##
## LEF for PtnCells ;
## created by Innovus v15.23-s045_1 on Mon Mar  9 14:37:11 2026
##

VERSION 5.8 ;

BUSBITCHARS "[]" ;
DIVIDERCHAR "/" ;

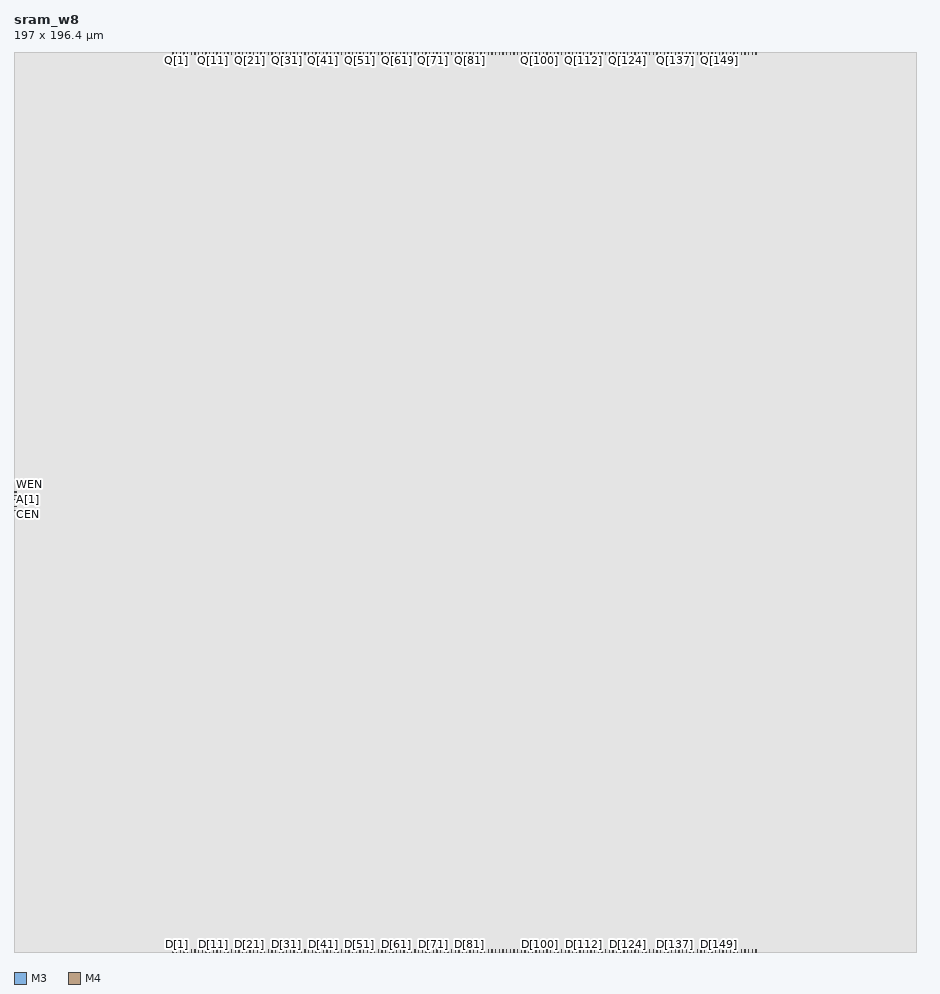
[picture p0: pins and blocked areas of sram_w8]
MACRO sram_w8
  CLASS BLOCK ;
  SIZE 197.0000 BY 196.4000 ;
  FOREIGN sram_w8 0.0000 0.0000 ;
  ORIGIN 0 0 ;
  SYMMETRY X Y R90 ;
  PIN CLK
    DIRECTION INPUT ;
    USE SIGNAL ;
    PORT
      LAYER M3 ;
        RECT 0.0000 96.3500 0.6000 96.4500 ;
    END
  END CLK
  PIN D[159]
    DIRECTION INPUT ;
    USE SIGNAL ;
    PORT
      LAYER M4 ;
        RECT 161.8500 0.0000 161.9500 0.6000 ;
    END
  END D[159]
  PIN D[158]
    DIRECTION INPUT ;
    USE SIGNAL ;
    PORT
      LAYER M4 ;
        RECT 161.0500 0.0000 161.1500 0.6000 ;
    END
  END D[158]
  PIN D[157]
    DIRECTION INPUT ;
    USE SIGNAL ;
    PORT
      LAYER M4 ;
        RECT 160.2500 0.0000 160.3500 0.6000 ;
    END
  END D[157]
  PIN D[156]
    DIRECTION INPUT ;
    USE SIGNAL ;
    PORT
      LAYER M4 ;
        RECT 159.4500 0.0000 159.5500 0.6000 ;
    END
  END D[156]
  PIN D[155]
    DIRECTION INPUT ;
    USE SIGNAL ;
    PORT
      LAYER M4 ;
        RECT 158.6500 0.0000 158.7500 0.6000 ;
    END
  END D[155]
  PIN D[154]
    DIRECTION INPUT ;
    USE SIGNAL ;
    PORT
      LAYER M4 ;
        RECT 157.8500 0.0000 157.9500 0.6000 ;
    END
  END D[154]
  PIN D[153]
    DIRECTION INPUT ;
    USE SIGNAL ;
    PORT
      LAYER M4 ;
        RECT 157.0500 0.0000 157.1500 0.6000 ;
    END
  END D[153]
  PIN D[152]
    DIRECTION INPUT ;
    USE SIGNAL ;
    PORT
      LAYER M4 ;
        RECT 156.2500 0.0000 156.3500 0.6000 ;
    END
  END D[152]
  PIN D[151]
    DIRECTION INPUT ;
    USE SIGNAL ;
    PORT
      LAYER M4 ;
        RECT 155.4500 0.0000 155.5500 0.6000 ;
    END
  END D[151]
  PIN D[150]
    DIRECTION INPUT ;
    USE SIGNAL ;
    PORT
      LAYER M4 ;
        RECT 154.6500 0.0000 154.7500 0.6000 ;
    END
  END D[150]
  PIN D[149]
    DIRECTION INPUT ;
    USE SIGNAL ;
    PORT
      LAYER M4 ;
        RECT 153.8500 0.0000 153.9500 0.6000 ;
    END
  END D[149]
  PIN D[148]
    DIRECTION INPUT ;
    USE SIGNAL ;
    PORT
      LAYER M4 ;
        RECT 153.0500 0.0000 153.1500 0.6000 ;
    END
  END D[148]
  PIN D[147]
    DIRECTION INPUT ;
    USE SIGNAL ;
    PORT
      LAYER M4 ;
        RECT 152.2500 0.0000 152.3500 0.6000 ;
    END
  END D[147]
  PIN D[146]
    DIRECTION INPUT ;
    USE SIGNAL ;
    PORT
      LAYER M4 ;
        RECT 151.4500 0.0000 151.5500 0.6000 ;
    END
  END D[146]
  PIN D[145]
    DIRECTION INPUT ;
    USE SIGNAL ;
    PORT
      LAYER M4 ;
        RECT 150.6500 0.0000 150.7500 0.6000 ;
    END
  END D[145]
  PIN D[144]
    DIRECTION INPUT ;
    USE SIGNAL ;
    PORT
      LAYER M4 ;
        RECT 149.8500 0.0000 149.9500 0.6000 ;
    END
  END D[144]
  PIN D[143]
    DIRECTION INPUT ;
    USE SIGNAL ;
    PORT
      LAYER M4 ;
        RECT 149.0500 0.0000 149.1500 0.6000 ;
    END
  END D[143]
  PIN D[142]
    DIRECTION INPUT ;
    USE SIGNAL ;
    PORT
      LAYER M4 ;
        RECT 148.2500 0.0000 148.3500 0.6000 ;
    END
  END D[142]
  PIN D[141]
    DIRECTION INPUT ;
    USE SIGNAL ;
    PORT
      LAYER M4 ;
        RECT 147.4500 0.0000 147.5500 0.6000 ;
    END
  END D[141]
  PIN D[140]
    DIRECTION INPUT ;
    USE SIGNAL ;
    PORT
      LAYER M4 ;
        RECT 146.6500 0.0000 146.7500 0.6000 ;
    END
  END D[140]
  PIN D[139]
    DIRECTION INPUT ;
    USE SIGNAL ;
    PORT
      LAYER M4 ;
        RECT 145.8500 0.0000 145.9500 0.6000 ;
    END
  END D[139]
  PIN D[138]
    DIRECTION INPUT ;
    USE SIGNAL ;
    PORT
      LAYER M4 ;
        RECT 145.0500 0.0000 145.1500 0.6000 ;
    END
  END D[138]
  PIN D[137]
    DIRECTION INPUT ;
    USE SIGNAL ;
    PORT
      LAYER M4 ;
        RECT 144.2500 0.0000 144.3500 0.6000 ;
    END
  END D[137]
  PIN D[136]
    DIRECTION INPUT ;
    USE SIGNAL ;
    PORT
      LAYER M4 ;
        RECT 143.4500 0.0000 143.5500 0.6000 ;
    END
  END D[136]
  PIN D[135]
    DIRECTION INPUT ;
    USE SIGNAL ;
    PORT
      LAYER M4 ;
        RECT 142.6500 0.0000 142.7500 0.6000 ;
    END
  END D[135]
  PIN D[134]
    DIRECTION INPUT ;
    USE SIGNAL ;
    PORT
      LAYER M4 ;
        RECT 141.8500 0.0000 141.9500 0.6000 ;
    END
  END D[134]
  PIN D[133]
    DIRECTION INPUT ;
    USE SIGNAL ;
    PORT
      LAYER M4 ;
        RECT 141.0500 0.0000 141.1500 0.6000 ;
    END
  END D[133]
  PIN D[132]
    DIRECTION INPUT ;
    USE SIGNAL ;
    PORT
      LAYER M4 ;
        RECT 140.2500 0.0000 140.3500 0.6000 ;
    END
  END D[132]
  PIN D[131]
    DIRECTION INPUT ;
    USE SIGNAL ;
    PORT
      LAYER M4 ;
        RECT 139.4500 0.0000 139.5500 0.6000 ;
    END
  END D[131]
  PIN D[130]
    DIRECTION INPUT ;
    USE SIGNAL ;
    PORT
      LAYER M4 ;
        RECT 138.6500 0.0000 138.7500 0.6000 ;
    END
  END D[130]
  PIN D[129]
    DIRECTION INPUT ;
    USE SIGNAL ;
    PORT
      LAYER M4 ;
        RECT 137.8500 0.0000 137.9500 0.6000 ;
    END
  END D[129]
  PIN D[128]
    DIRECTION INPUT ;
    USE SIGNAL ;
    PORT
      LAYER M4 ;
        RECT 137.0500 0.0000 137.1500 0.6000 ;
    END
  END D[128]
  PIN D[127]
    DIRECTION INPUT ;
    USE SIGNAL ;
    PORT
      LAYER M4 ;
        RECT 136.2500 0.0000 136.3500 0.6000 ;
    END
  END D[127]
  PIN D[126]
    DIRECTION INPUT ;
    USE SIGNAL ;
    PORT
      LAYER M4 ;
        RECT 135.4500 0.0000 135.5500 0.6000 ;
    END
  END D[126]
  PIN D[125]
    DIRECTION INPUT ;
    USE SIGNAL ;
    PORT
      LAYER M4 ;
        RECT 134.6500 0.0000 134.7500 0.6000 ;
    END
  END D[125]
  PIN D[124]
    DIRECTION INPUT ;
    USE SIGNAL ;
    PORT
      LAYER M4 ;
        RECT 133.8500 0.0000 133.9500 0.6000 ;
    END
  END D[124]
  PIN D[123]
    DIRECTION INPUT ;
    USE SIGNAL ;
    PORT
      LAYER M4 ;
        RECT 133.0500 0.0000 133.1500 0.6000 ;
    END
  END D[123]
  PIN D[122]
    DIRECTION INPUT ;
    USE SIGNAL ;
    PORT
      LAYER M4 ;
        RECT 132.2500 0.0000 132.3500 0.6000 ;
    END
  END D[122]
  PIN D[121]
    DIRECTION INPUT ;
    USE SIGNAL ;
    PORT
      LAYER M4 ;
        RECT 131.4500 0.0000 131.5500 0.6000 ;
    END
  END D[121]
  PIN D[120]
    DIRECTION INPUT ;
    USE SIGNAL ;
    PORT
      LAYER M4 ;
        RECT 130.6500 0.0000 130.7500 0.6000 ;
    END
  END D[120]
  PIN D[119]
    DIRECTION INPUT ;
    USE SIGNAL ;
    PORT
      LAYER M4 ;
        RECT 129.8500 0.0000 129.9500 0.6000 ;
    END
  END D[119]
  PIN D[118]
    DIRECTION INPUT ;
    USE SIGNAL ;
    PORT
      LAYER M4 ;
        RECT 129.0500 0.0000 129.1500 0.6000 ;
    END
  END D[118]
  PIN D[117]
    DIRECTION INPUT ;
    USE SIGNAL ;
    PORT
      LAYER M4 ;
        RECT 128.2500 0.0000 128.3500 0.6000 ;
    END
  END D[117]
  PIN D[116]
    DIRECTION INPUT ;
    USE SIGNAL ;
    PORT
      LAYER M4 ;
        RECT 127.4500 0.0000 127.5500 0.6000 ;
    END
  END D[116]
  PIN D[115]
    DIRECTION INPUT ;
    USE SIGNAL ;
    PORT
      LAYER M4 ;
        RECT 126.6500 0.0000 126.7500 0.6000 ;
    END
  END D[115]
  PIN D[114]
    DIRECTION INPUT ;
    USE SIGNAL ;
    PORT
      LAYER M4 ;
        RECT 125.8500 0.0000 125.9500 0.6000 ;
    END
  END D[114]
  PIN D[113]
    DIRECTION INPUT ;
    USE SIGNAL ;
    PORT
      LAYER M4 ;
        RECT 125.0500 0.0000 125.1500 0.6000 ;
    END
  END D[113]
  PIN D[112]
    DIRECTION INPUT ;
    USE SIGNAL ;
    PORT
      LAYER M4 ;
        RECT 124.2500 0.0000 124.3500 0.6000 ;
    END
  END D[112]
  PIN D[111]
    DIRECTION INPUT ;
    USE SIGNAL ;
    PORT
      LAYER M4 ;
        RECT 123.4500 0.0000 123.5500 0.6000 ;
    END
  END D[111]
  PIN D[110]
    DIRECTION INPUT ;
    USE SIGNAL ;
    PORT
      LAYER M4 ;
        RECT 122.6500 0.0000 122.7500 0.6000 ;
    END
  END D[110]
  PIN D[109]
    DIRECTION INPUT ;
    USE SIGNAL ;
    PORT
      LAYER M4 ;
        RECT 121.8500 0.0000 121.9500 0.6000 ;
    END
  END D[109]
  PIN D[108]
    DIRECTION INPUT ;
    USE SIGNAL ;
    PORT
      LAYER M4 ;
        RECT 121.0500 0.0000 121.1500 0.6000 ;
    END
  END D[108]
  PIN D[107]
    DIRECTION INPUT ;
    USE SIGNAL ;
    PORT
      LAYER M4 ;
        RECT 120.2500 0.0000 120.3500 0.6000 ;
    END
  END D[107]
  PIN D[106]
    DIRECTION INPUT ;
    USE SIGNAL ;
    PORT
      LAYER M4 ;
        RECT 119.4500 0.0000 119.5500 0.6000 ;
    END
  END D[106]
  PIN D[105]
    DIRECTION INPUT ;
    USE SIGNAL ;
    PORT
      LAYER M4 ;
        RECT 118.6500 0.0000 118.7500 0.6000 ;
    END
  END D[105]
  PIN D[104]
    DIRECTION INPUT ;
    USE SIGNAL ;
    PORT
      LAYER M4 ;
        RECT 117.8500 0.0000 117.9500 0.6000 ;
    END
  END D[104]
  PIN D[103]
    DIRECTION INPUT ;
    USE SIGNAL ;
    PORT
      LAYER M4 ;
        RECT 117.0500 0.0000 117.1500 0.6000 ;
    END
  END D[103]
  PIN D[102]
    DIRECTION INPUT ;
    USE SIGNAL ;
    PORT
      LAYER M4 ;
        RECT 116.2500 0.0000 116.3500 0.6000 ;
    END
  END D[102]
  PIN D[101]
    DIRECTION INPUT ;
    USE SIGNAL ;
    PORT
      LAYER M4 ;
        RECT 115.4500 0.0000 115.5500 0.6000 ;
    END
  END D[101]
  PIN D[100]
    DIRECTION INPUT ;
    USE SIGNAL ;
    PORT
      LAYER M4 ;
        RECT 114.6500 0.0000 114.7500 0.6000 ;
    END
  END D[100]
  PIN D[99]
    DIRECTION INPUT ;
    USE SIGNAL ;
    PORT
      LAYER M4 ;
        RECT 113.8500 0.0000 113.9500 0.6000 ;
    END
  END D[99]
  PIN D[98]
    DIRECTION INPUT ;
    USE SIGNAL ;
    PORT
      LAYER M4 ;
        RECT 113.0500 0.0000 113.1500 0.6000 ;
    END
  END D[98]
  PIN D[97]
    DIRECTION INPUT ;
    USE SIGNAL ;
    PORT
      LAYER M4 ;
        RECT 112.2500 0.0000 112.3500 0.6000 ;
    END
  END D[97]
  PIN D[96]
    DIRECTION INPUT ;
    USE SIGNAL ;
    PORT
      LAYER M4 ;
        RECT 111.4500 0.0000 111.5500 0.6000 ;
    END
  END D[96]
  PIN D[95]
    DIRECTION INPUT ;
    USE SIGNAL ;
    PORT
      LAYER M4 ;
        RECT 110.6500 0.0000 110.7500 0.6000 ;
    END
  END D[95]
  PIN D[94]
    DIRECTION INPUT ;
    USE SIGNAL ;
    PORT
      LAYER M4 ;
        RECT 109.8500 0.0000 109.9500 0.6000 ;
    END
  END D[94]
  PIN D[93]
    DIRECTION INPUT ;
    USE SIGNAL ;
    PORT
      LAYER M4 ;
        RECT 109.0500 0.0000 109.1500 0.6000 ;
    END
  END D[93]
  PIN D[92]
    DIRECTION INPUT ;
    USE SIGNAL ;
    PORT
      LAYER M4 ;
        RECT 108.2500 0.0000 108.3500 0.6000 ;
    END
  END D[92]
  PIN D[91]
    DIRECTION INPUT ;
    USE SIGNAL ;
    PORT
      LAYER M4 ;
        RECT 107.4500 0.0000 107.5500 0.6000 ;
    END
  END D[91]
  PIN D[90]
    DIRECTION INPUT ;
    USE SIGNAL ;
    PORT
      LAYER M4 ;
        RECT 106.6500 0.0000 106.7500 0.6000 ;
    END
  END D[90]
  PIN D[89]
    DIRECTION INPUT ;
    USE SIGNAL ;
    PORT
      LAYER M4 ;
        RECT 105.8500 0.0000 105.9500 0.6000 ;
    END
  END D[89]
  PIN D[88]
    DIRECTION INPUT ;
    USE SIGNAL ;
    PORT
      LAYER M4 ;
        RECT 105.0500 0.0000 105.1500 0.6000 ;
    END
  END D[88]
  PIN D[87]
    DIRECTION INPUT ;
    USE SIGNAL ;
    PORT
      LAYER M4 ;
        RECT 104.2500 0.0000 104.3500 0.6000 ;
    END
  END D[87]
  PIN D[86]
    DIRECTION INPUT ;
    USE SIGNAL ;
    PORT
      LAYER M4 ;
        RECT 103.4500 0.0000 103.5500 0.6000 ;
    END
  END D[86]
  PIN D[85]
    DIRECTION INPUT ;
    USE SIGNAL ;
    PORT
      LAYER M4 ;
        RECT 102.6500 0.0000 102.7500 0.6000 ;
    END
  END D[85]
  PIN D[84]
    DIRECTION INPUT ;
    USE SIGNAL ;
    PORT
      LAYER M4 ;
        RECT 101.8500 0.0000 101.9500 0.6000 ;
    END
  END D[84]
  PIN D[83]
    DIRECTION INPUT ;
    USE SIGNAL ;
    PORT
      LAYER M4 ;
        RECT 101.0500 0.0000 101.1500 0.6000 ;
    END
  END D[83]
  PIN D[82]
    DIRECTION INPUT ;
    USE SIGNAL ;
    PORT
      LAYER M4 ;
        RECT 100.2500 0.0000 100.3500 0.6000 ;
    END
  END D[82]
  PIN D[81]
    DIRECTION INPUT ;
    USE SIGNAL ;
    PORT
      LAYER M4 ;
        RECT 99.4500 0.0000 99.5500 0.6000 ;
    END
  END D[81]
  PIN D[80]
    DIRECTION INPUT ;
    USE SIGNAL ;
    PORT
      LAYER M4 ;
        RECT 98.6500 0.0000 98.7500 0.6000 ;
    END
  END D[80]
  PIN D[79]
    DIRECTION INPUT ;
    USE SIGNAL ;
    PORT
      LAYER M4 ;
        RECT 97.8500 0.0000 97.9500 0.6000 ;
    END
  END D[79]
  PIN D[78]
    DIRECTION INPUT ;
    USE SIGNAL ;
    PORT
      LAYER M4 ;
        RECT 97.0500 0.0000 97.1500 0.6000 ;
    END
  END D[78]
  PIN D[77]
    DIRECTION INPUT ;
    USE SIGNAL ;
    PORT
      LAYER M4 ;
        RECT 96.2500 0.0000 96.3500 0.6000 ;
    END
  END D[77]
  PIN D[76]
    DIRECTION INPUT ;
    USE SIGNAL ;
    PORT
      LAYER M4 ;
        RECT 95.4500 0.0000 95.5500 0.6000 ;
    END
  END D[76]
  PIN D[75]
    DIRECTION INPUT ;
    USE SIGNAL ;
    PORT
      LAYER M4 ;
        RECT 94.6500 0.0000 94.7500 0.6000 ;
    END
  END D[75]
  PIN D[74]
    DIRECTION INPUT ;
    USE SIGNAL ;
    PORT
      LAYER M4 ;
        RECT 93.8500 0.0000 93.9500 0.6000 ;
    END
  END D[74]
  PIN D[73]
    DIRECTION INPUT ;
    USE SIGNAL ;
    PORT
      LAYER M4 ;
        RECT 93.0500 0.0000 93.1500 0.6000 ;
    END
  END D[73]
  PIN D[72]
    DIRECTION INPUT ;
    USE SIGNAL ;
    PORT
      LAYER M4 ;
        RECT 92.2500 0.0000 92.3500 0.6000 ;
    END
  END D[72]
  PIN D[71]
    DIRECTION INPUT ;
    USE SIGNAL ;
    PORT
      LAYER M4 ;
        RECT 91.4500 0.0000 91.5500 0.6000 ;
    END
  END D[71]
  PIN D[70]
    DIRECTION INPUT ;
    USE SIGNAL ;
    PORT
      LAYER M4 ;
        RECT 90.6500 0.0000 90.7500 0.6000 ;
    END
  END D[70]
  PIN D[69]
    DIRECTION INPUT ;
    USE SIGNAL ;
    PORT
      LAYER M4 ;
        RECT 89.8500 0.0000 89.9500 0.6000 ;
    END
  END D[69]
  PIN D[68]
    DIRECTION INPUT ;
    USE SIGNAL ;
    PORT
      LAYER M4 ;
        RECT 89.0500 0.0000 89.1500 0.6000 ;
    END
  END D[68]
  PIN D[67]
    DIRECTION INPUT ;
    USE SIGNAL ;
    PORT
      LAYER M4 ;
        RECT 88.2500 0.0000 88.3500 0.6000 ;
    END
  END D[67]
  PIN D[66]
    DIRECTION INPUT ;
    USE SIGNAL ;
    PORT
      LAYER M4 ;
        RECT 87.4500 0.0000 87.5500 0.6000 ;
    END
  END D[66]
  PIN D[65]
    DIRECTION INPUT ;
    USE SIGNAL ;
    PORT
      LAYER M4 ;
        RECT 86.6500 0.0000 86.7500 0.6000 ;
    END
  END D[65]
  PIN D[64]
    DIRECTION INPUT ;
    USE SIGNAL ;
    PORT
      LAYER M4 ;
        RECT 85.8500 0.0000 85.9500 0.6000 ;
    END
  END D[64]
  PIN D[63]
    DIRECTION INPUT ;
    USE SIGNAL ;
    PORT
      LAYER M4 ;
        RECT 85.0500 0.0000 85.1500 0.6000 ;
    END
  END D[63]
  PIN D[62]
    DIRECTION INPUT ;
    USE SIGNAL ;
    PORT
      LAYER M4 ;
        RECT 84.2500 0.0000 84.3500 0.6000 ;
    END
  END D[62]
  PIN D[61]
    DIRECTION INPUT ;
    USE SIGNAL ;
    PORT
      LAYER M4 ;
        RECT 83.4500 0.0000 83.5500 0.6000 ;
    END
  END D[61]
  PIN D[60]
    DIRECTION INPUT ;
    USE SIGNAL ;
    PORT
      LAYER M4 ;
        RECT 82.6500 0.0000 82.7500 0.6000 ;
    END
  END D[60]
  PIN D[59]
    DIRECTION INPUT ;
    USE SIGNAL ;
    PORT
      LAYER M4 ;
        RECT 81.8500 0.0000 81.9500 0.6000 ;
    END
  END D[59]
  PIN D[58]
    DIRECTION INPUT ;
    USE SIGNAL ;
    PORT
      LAYER M4 ;
        RECT 81.0500 0.0000 81.1500 0.6000 ;
    END
  END D[58]
  PIN D[57]
    DIRECTION INPUT ;
    USE SIGNAL ;
    PORT
      LAYER M4 ;
        RECT 80.2500 0.0000 80.3500 0.6000 ;
    END
  END D[57]
  PIN D[56]
    DIRECTION INPUT ;
    USE SIGNAL ;
    PORT
      LAYER M4 ;
        RECT 79.4500 0.0000 79.5500 0.6000 ;
    END
  END D[56]
  PIN D[55]
    DIRECTION INPUT ;
    USE SIGNAL ;
    PORT
      LAYER M4 ;
        RECT 78.6500 0.0000 78.7500 0.6000 ;
    END
  END D[55]
  PIN D[54]
    DIRECTION INPUT ;
    USE SIGNAL ;
    PORT
      LAYER M4 ;
        RECT 77.8500 0.0000 77.9500 0.6000 ;
    END
  END D[54]
  PIN D[53]
    DIRECTION INPUT ;
    USE SIGNAL ;
    PORT
      LAYER M4 ;
        RECT 77.0500 0.0000 77.1500 0.6000 ;
    END
  END D[53]
  PIN D[52]
    DIRECTION INPUT ;
    USE SIGNAL ;
    PORT
      LAYER M4 ;
        RECT 76.2500 0.0000 76.3500 0.6000 ;
    END
  END D[52]
  PIN D[51]
    DIRECTION INPUT ;
    USE SIGNAL ;
    PORT
      LAYER M4 ;
        RECT 75.4500 0.0000 75.5500 0.6000 ;
    END
  END D[51]
  PIN D[50]
    DIRECTION INPUT ;
    USE SIGNAL ;
    PORT
      LAYER M4 ;
        RECT 74.6500 0.0000 74.7500 0.6000 ;
    END
  END D[50]
  PIN D[49]
    DIRECTION INPUT ;
    USE SIGNAL ;
    PORT
      LAYER M4 ;
        RECT 73.8500 0.0000 73.9500 0.6000 ;
    END
  END D[49]
  PIN D[48]
    DIRECTION INPUT ;
    USE SIGNAL ;
    PORT
      LAYER M4 ;
        RECT 73.0500 0.0000 73.1500 0.6000 ;
    END
  END D[48]
  PIN D[47]
    DIRECTION INPUT ;
    USE SIGNAL ;
    PORT
      LAYER M4 ;
        RECT 72.2500 0.0000 72.3500 0.6000 ;
    END
  END D[47]
  PIN D[46]
    DIRECTION INPUT ;
    USE SIGNAL ;
    PORT
      LAYER M4 ;
        RECT 71.4500 0.0000 71.5500 0.6000 ;
    END
  END D[46]
  PIN D[45]
    DIRECTION INPUT ;
    USE SIGNAL ;
    PORT
      LAYER M4 ;
        RECT 70.6500 0.0000 70.7500 0.6000 ;
    END
  END D[45]
  PIN D[44]
    DIRECTION INPUT ;
    USE SIGNAL ;
    PORT
      LAYER M4 ;
        RECT 69.8500 0.0000 69.9500 0.6000 ;
    END
  END D[44]
  PIN D[43]
    DIRECTION INPUT ;
    USE SIGNAL ;
    PORT
      LAYER M4 ;
        RECT 69.0500 0.0000 69.1500 0.6000 ;
    END
  END D[43]
  PIN D[42]
    DIRECTION INPUT ;
    USE SIGNAL ;
    PORT
      LAYER M4 ;
        RECT 68.2500 0.0000 68.3500 0.6000 ;
    END
  END D[42]
  PIN D[41]
    DIRECTION INPUT ;
    USE SIGNAL ;
    PORT
      LAYER M4 ;
        RECT 67.4500 0.0000 67.5500 0.6000 ;
    END
  END D[41]
  PIN D[40]
    DIRECTION INPUT ;
    USE SIGNAL ;
    PORT
      LAYER M4 ;
        RECT 66.6500 0.0000 66.7500 0.6000 ;
    END
  END D[40]
  PIN D[39]
    DIRECTION INPUT ;
    USE SIGNAL ;
    PORT
      LAYER M4 ;
        RECT 65.8500 0.0000 65.9500 0.6000 ;
    END
  END D[39]
  PIN D[38]
    DIRECTION INPUT ;
    USE SIGNAL ;
    PORT
      LAYER M4 ;
        RECT 65.0500 0.0000 65.1500 0.6000 ;
    END
  END D[38]
  PIN D[37]
    DIRECTION INPUT ;
    USE SIGNAL ;
    PORT
      LAYER M4 ;
        RECT 64.2500 0.0000 64.3500 0.6000 ;
    END
  END D[37]
  PIN D[36]
    DIRECTION INPUT ;
    USE SIGNAL ;
    PORT
      LAYER M4 ;
        RECT 63.4500 0.0000 63.5500 0.6000 ;
    END
  END D[36]
  PIN D[35]
    DIRECTION INPUT ;
    USE SIGNAL ;
    PORT
      LAYER M4 ;
        RECT 62.6500 0.0000 62.7500 0.6000 ;
    END
  END D[35]
  PIN D[34]
    DIRECTION INPUT ;
    USE SIGNAL ;
    PORT
      LAYER M4 ;
        RECT 61.8500 0.0000 61.9500 0.6000 ;
    END
  END D[34]
  PIN D[33]
    DIRECTION INPUT ;
    USE SIGNAL ;
    PORT
      LAYER M4 ;
        RECT 61.0500 0.0000 61.1500 0.6000 ;
    END
  END D[33]
  PIN D[32]
    DIRECTION INPUT ;
    USE SIGNAL ;
    PORT
      LAYER M4 ;
        RECT 60.2500 0.0000 60.3500 0.6000 ;
    END
  END D[32]
  PIN D[31]
    DIRECTION INPUT ;
    USE SIGNAL ;
    PORT
      LAYER M4 ;
        RECT 59.4500 0.0000 59.5500 0.6000 ;
    END
  END D[31]
  PIN D[30]
    DIRECTION INPUT ;
    USE SIGNAL ;
    PORT
      LAYER M4 ;
        RECT 58.6500 0.0000 58.7500 0.6000 ;
    END
  END D[30]
  PIN D[29]
    DIRECTION INPUT ;
    USE SIGNAL ;
    PORT
      LAYER M4 ;
        RECT 57.8500 0.0000 57.9500 0.6000 ;
    END
  END D[29]
  PIN D[28]
    DIRECTION INPUT ;
    USE SIGNAL ;
    PORT
      LAYER M4 ;
        RECT 57.0500 0.0000 57.1500 0.6000 ;
    END
  END D[28]
  PIN D[27]
    DIRECTION INPUT ;
    USE SIGNAL ;
    PORT
      LAYER M4 ;
        RECT 56.2500 0.0000 56.3500 0.6000 ;
    END
  END D[27]
  PIN D[26]
    DIRECTION INPUT ;
    USE SIGNAL ;
    PORT
      LAYER M4 ;
        RECT 55.4500 0.0000 55.5500 0.6000 ;
    END
  END D[26]
  PIN D[25]
    DIRECTION INPUT ;
    USE SIGNAL ;
    PORT
      LAYER M4 ;
        RECT 54.6500 0.0000 54.7500 0.6000 ;
    END
  END D[25]
  PIN D[24]
    DIRECTION INPUT ;
    USE SIGNAL ;
    PORT
      LAYER M4 ;
        RECT 53.8500 0.0000 53.9500 0.6000 ;
    END
  END D[24]
  PIN D[23]
    DIRECTION INPUT ;
    USE SIGNAL ;
    PORT
      LAYER M4 ;
        RECT 53.0500 0.0000 53.1500 0.6000 ;
    END
  END D[23]
  PIN D[22]
    DIRECTION INPUT ;
    USE SIGNAL ;
    PORT
      LAYER M4 ;
        RECT 52.2500 0.0000 52.3500 0.6000 ;
    END
  END D[22]
  PIN D[21]
    DIRECTION INPUT ;
    USE SIGNAL ;
    PORT
      LAYER M4 ;
        RECT 51.4500 0.0000 51.5500 0.6000 ;
    END
  END D[21]
  PIN D[20]
    DIRECTION INPUT ;
    USE SIGNAL ;
    PORT
      LAYER M4 ;
        RECT 50.6500 0.0000 50.7500 0.6000 ;
    END
  END D[20]
  PIN D[19]
    DIRECTION INPUT ;
    USE SIGNAL ;
    PORT
      LAYER M4 ;
        RECT 49.8500 0.0000 49.9500 0.6000 ;
    END
  END D[19]
  PIN D[18]
    DIRECTION INPUT ;
    USE SIGNAL ;
    PORT
      LAYER M4 ;
        RECT 49.0500 0.0000 49.1500 0.6000 ;
    END
  END D[18]
  PIN D[17]
    DIRECTION INPUT ;
    USE SIGNAL ;
    PORT
      LAYER M4 ;
        RECT 48.2500 0.0000 48.3500 0.6000 ;
    END
  END D[17]
  PIN D[16]
    DIRECTION INPUT ;
    USE SIGNAL ;
    PORT
      LAYER M4 ;
        RECT 47.4500 0.0000 47.5500 0.6000 ;
    END
  END D[16]
  PIN D[15]
    DIRECTION INPUT ;
    USE SIGNAL ;
    PORT
      LAYER M4 ;
        RECT 46.6500 0.0000 46.7500 0.6000 ;
    END
  END D[15]
  PIN D[14]
    DIRECTION INPUT ;
    USE SIGNAL ;
    PORT
      LAYER M4 ;
        RECT 45.8500 0.0000 45.9500 0.6000 ;
    END
  END D[14]
  PIN D[13]
    DIRECTION INPUT ;
    USE SIGNAL ;
    PORT
      LAYER M4 ;
        RECT 45.0500 0.0000 45.1500 0.6000 ;
    END
  END D[13]
  PIN D[12]
    DIRECTION INPUT ;
    USE SIGNAL ;
    PORT
      LAYER M4 ;
        RECT 44.2500 0.0000 44.3500 0.6000 ;
    END
  END D[12]
  PIN D[11]
    DIRECTION INPUT ;
    USE SIGNAL ;
    PORT
      LAYER M4 ;
        RECT 43.4500 0.0000 43.5500 0.6000 ;
    END
  END D[11]
  PIN D[10]
    DIRECTION INPUT ;
    USE SIGNAL ;
    PORT
      LAYER M4 ;
        RECT 42.6500 0.0000 42.7500 0.6000 ;
    END
  END D[10]
  PIN D[9]
    DIRECTION INPUT ;
    USE SIGNAL ;
    PORT
      LAYER M4 ;
        RECT 41.8500 0.0000 41.9500 0.6000 ;
    END
  END D[9]
  PIN D[8]
    DIRECTION INPUT ;
    USE SIGNAL ;
    PORT
      LAYER M4 ;
        RECT 41.0500 0.0000 41.1500 0.6000 ;
    END
  END D[8]
  PIN D[7]
    DIRECTION INPUT ;
    USE SIGNAL ;
    PORT
      LAYER M4 ;
        RECT 40.2500 0.0000 40.3500 0.6000 ;
    END
  END D[7]
  PIN D[6]
    DIRECTION INPUT ;
    USE SIGNAL ;
    PORT
      LAYER M4 ;
        RECT 39.4500 0.0000 39.5500 0.6000 ;
    END
  END D[6]
  PIN D[5]
    DIRECTION INPUT ;
    USE SIGNAL ;
    PORT
      LAYER M4 ;
        RECT 38.6500 0.0000 38.7500 0.6000 ;
    END
  END D[5]
  PIN D[4]
    DIRECTION INPUT ;
    USE SIGNAL ;
    PORT
      LAYER M4 ;
        RECT 37.8500 0.0000 37.9500 0.6000 ;
    END
  END D[4]
  PIN D[3]
    DIRECTION INPUT ;
    USE SIGNAL ;
    PORT
      LAYER M4 ;
        RECT 37.0500 0.0000 37.1500 0.6000 ;
    END
  END D[3]
  PIN D[2]
    DIRECTION INPUT ;
    USE SIGNAL ;
    PORT
      LAYER M4 ;
        RECT 36.2500 0.0000 36.3500 0.6000 ;
    END
  END D[2]
  PIN D[1]
    DIRECTION INPUT ;
    USE SIGNAL ;
    PORT
      LAYER M4 ;
        RECT 35.4500 0.0000 35.5500 0.6000 ;
    END
  END D[1]
  PIN D[0]
    DIRECTION INPUT ;
    USE SIGNAL ;
    PORT
      LAYER M4 ;
        RECT 34.6500 0.0000 34.7500 0.6000 ;
    END
  END D[0]
  PIN Q[159]
    DIRECTION OUTPUT ;
    USE SIGNAL ;
    PORT
      LAYER M4 ;
        RECT 161.8500 195.8000 161.9500 196.4000 ;
    END
  END Q[159]
  PIN Q[158]
    DIRECTION OUTPUT ;
    USE SIGNAL ;
    PORT
      LAYER M4 ;
        RECT 161.0500 195.8000 161.1500 196.4000 ;
    END
  END Q[158]
  PIN Q[157]
    DIRECTION OUTPUT ;
    USE SIGNAL ;
    PORT
      LAYER M4 ;
        RECT 160.2500 195.8000 160.3500 196.4000 ;
    END
  END Q[157]
  PIN Q[156]
    DIRECTION OUTPUT ;
    USE SIGNAL ;
    PORT
      LAYER M4 ;
        RECT 159.4500 195.8000 159.5500 196.4000 ;
    END
  END Q[156]
  PIN Q[155]
    DIRECTION OUTPUT ;
    USE SIGNAL ;
    PORT
      LAYER M4 ;
        RECT 158.6500 195.8000 158.7500 196.4000 ;
    END
  END Q[155]
  PIN Q[154]
    DIRECTION OUTPUT ;
    USE SIGNAL ;
    PORT
      LAYER M4 ;
        RECT 157.8500 195.8000 157.9500 196.4000 ;
    END
  END Q[154]
  PIN Q[153]
    DIRECTION OUTPUT ;
    USE SIGNAL ;
    PORT
      LAYER M4 ;
        RECT 157.0500 195.8000 157.1500 196.4000 ;
    END
  END Q[153]
  PIN Q[152]
    DIRECTION OUTPUT ;
    USE SIGNAL ;
    PORT
      LAYER M4 ;
        RECT 156.2500 195.8000 156.3500 196.4000 ;
    END
  END Q[152]
  PIN Q[151]
    DIRECTION OUTPUT ;
    USE SIGNAL ;
    PORT
      LAYER M4 ;
        RECT 155.4500 195.8000 155.5500 196.4000 ;
    END
  END Q[151]
  PIN Q[150]
    DIRECTION OUTPUT ;
    USE SIGNAL ;
    PORT
      LAYER M4 ;
        RECT 154.6500 195.8000 154.7500 196.4000 ;
    END
  END Q[150]
  PIN Q[149]
    DIRECTION OUTPUT ;
    USE SIGNAL ;
    PORT
      LAYER M4 ;
        RECT 153.8500 195.8000 153.9500 196.4000 ;
    END
  END Q[149]
  PIN Q[148]
    DIRECTION OUTPUT ;
    USE SIGNAL ;
    PORT
      LAYER M4 ;
        RECT 153.0500 195.8000 153.1500 196.4000 ;
    END
  END Q[148]
  PIN Q[147]
    DIRECTION OUTPUT ;
    USE SIGNAL ;
    PORT
      LAYER M4 ;
        RECT 152.2500 195.8000 152.3500 196.4000 ;
    END
  END Q[147]
  PIN Q[146]
    DIRECTION OUTPUT ;
    USE SIGNAL ;
    PORT
      LAYER M4 ;
        RECT 151.4500 195.8000 151.5500 196.4000 ;
    END
  END Q[146]
  PIN Q[145]
    DIRECTION OUTPUT ;
    USE SIGNAL ;
    PORT
      LAYER M4 ;
        RECT 150.6500 195.8000 150.7500 196.4000 ;
    END
  END Q[145]
  PIN Q[144]
    DIRECTION OUTPUT ;
    USE SIGNAL ;
    PORT
      LAYER M4 ;
        RECT 149.8500 195.8000 149.9500 196.4000 ;
    END
  END Q[144]
  PIN Q[143]
    DIRECTION OUTPUT ;
    USE SIGNAL ;
    PORT
      LAYER M4 ;
        RECT 149.0500 195.8000 149.1500 196.4000 ;
    END
  END Q[143]
  PIN Q[142]
    DIRECTION OUTPUT ;
    USE SIGNAL ;
    PORT
      LAYER M4 ;
        RECT 148.2500 195.8000 148.3500 196.4000 ;
    END
  END Q[142]
  PIN Q[141]
    DIRECTION OUTPUT ;
    USE SIGNAL ;
    PORT
      LAYER M4 ;
        RECT 147.4500 195.8000 147.5500 196.4000 ;
    END
  END Q[141]
  PIN Q[140]
    DIRECTION OUTPUT ;
    USE SIGNAL ;
    PORT
      LAYER M4 ;
        RECT 146.6500 195.8000 146.7500 196.4000 ;
    END
  END Q[140]
  PIN Q[139]
    DIRECTION OUTPUT ;
    USE SIGNAL ;
    PORT
      LAYER M4 ;
        RECT 145.8500 195.8000 145.9500 196.4000 ;
    END
  END Q[139]
  PIN Q[138]
    DIRECTION OUTPUT ;
    USE SIGNAL ;
    PORT
      LAYER M4 ;
        RECT 145.0500 195.8000 145.1500 196.4000 ;
    END
  END Q[138]
  PIN Q[137]
    DIRECTION OUTPUT ;
    USE SIGNAL ;
    PORT
      LAYER M4 ;
        RECT 144.2500 195.8000 144.3500 196.4000 ;
    END
  END Q[137]
  PIN Q[136]
    DIRECTION OUTPUT ;
    USE SIGNAL ;
    PORT
      LAYER M4 ;
        RECT 143.4500 195.8000 143.5500 196.4000 ;
    END
  END Q[136]
  PIN Q[135]
    DIRECTION OUTPUT ;
    USE SIGNAL ;
    PORT
      LAYER M4 ;
        RECT 142.6500 195.8000 142.7500 196.4000 ;
    END
  END Q[135]
  PIN Q[134]
    DIRECTION OUTPUT ;
    USE SIGNAL ;
    PORT
      LAYER M4 ;
        RECT 141.8500 195.8000 141.9500 196.4000 ;
    END
  END Q[134]
  PIN Q[133]
    DIRECTION OUTPUT ;
    USE SIGNAL ;
    PORT
      LAYER M4 ;
        RECT 141.0500 195.8000 141.1500 196.4000 ;
    END
  END Q[133]
  PIN Q[132]
    DIRECTION OUTPUT ;
    USE SIGNAL ;
    PORT
      LAYER M4 ;
        RECT 140.2500 195.8000 140.3500 196.4000 ;
    END
  END Q[132]
  PIN Q[131]
    DIRECTION OUTPUT ;
    USE SIGNAL ;
    PORT
      LAYER M4 ;
        RECT 139.4500 195.8000 139.5500 196.4000 ;
    END
  END Q[131]
  PIN Q[130]
    DIRECTION OUTPUT ;
    USE SIGNAL ;
    PORT
      LAYER M4 ;
        RECT 138.6500 195.8000 138.7500 196.4000 ;
    END
  END Q[130]
  PIN Q[129]
    DIRECTION OUTPUT ;
    USE SIGNAL ;
    PORT
      LAYER M4 ;
        RECT 137.8500 195.8000 137.9500 196.4000 ;
    END
  END Q[129]
  PIN Q[128]
    DIRECTION OUTPUT ;
    USE SIGNAL ;
    PORT
      LAYER M4 ;
        RECT 137.0500 195.8000 137.1500 196.4000 ;
    END
  END Q[128]
  PIN Q[127]
    DIRECTION OUTPUT ;
    USE SIGNAL ;
    PORT
      LAYER M4 ;
        RECT 136.2500 195.8000 136.3500 196.4000 ;
    END
  END Q[127]
  PIN Q[126]
    DIRECTION OUTPUT ;
    USE SIGNAL ;
    PORT
      LAYER M4 ;
        RECT 135.4500 195.8000 135.5500 196.4000 ;
    END
  END Q[126]
  PIN Q[125]
    DIRECTION OUTPUT ;
    USE SIGNAL ;
    PORT
      LAYER M4 ;
        RECT 134.6500 195.8000 134.7500 196.4000 ;
    END
  END Q[125]
  PIN Q[124]
    DIRECTION OUTPUT ;
    USE SIGNAL ;
    PORT
      LAYER M4 ;
        RECT 133.8500 195.8000 133.9500 196.4000 ;
    END
  END Q[124]
  PIN Q[123]
    DIRECTION OUTPUT ;
    USE SIGNAL ;
    PORT
      LAYER M4 ;
        RECT 133.0500 195.8000 133.1500 196.4000 ;
    END
  END Q[123]
  PIN Q[122]
    DIRECTION OUTPUT ;
    USE SIGNAL ;
    PORT
      LAYER M4 ;
        RECT 132.2500 195.8000 132.3500 196.4000 ;
    END
  END Q[122]
  PIN Q[121]
    DIRECTION OUTPUT ;
    USE SIGNAL ;
    PORT
      LAYER M4 ;
        RECT 131.4500 195.8000 131.5500 196.4000 ;
    END
  END Q[121]
  PIN Q[120]
    DIRECTION OUTPUT ;
    USE SIGNAL ;
    PORT
      LAYER M4 ;
        RECT 130.6500 195.8000 130.7500 196.4000 ;
    END
  END Q[120]
  PIN Q[119]
    DIRECTION OUTPUT ;
    USE SIGNAL ;
    PORT
      LAYER M4 ;
        RECT 129.8500 195.8000 129.9500 196.4000 ;
    END
  END Q[119]
  PIN Q[118]
    DIRECTION OUTPUT ;
    USE SIGNAL ;
    PORT
      LAYER M4 ;
        RECT 129.0500 195.8000 129.1500 196.4000 ;
    END
  END Q[118]
  PIN Q[117]
    DIRECTION OUTPUT ;
    USE SIGNAL ;
    PORT
      LAYER M4 ;
        RECT 128.2500 195.8000 128.3500 196.4000 ;
    END
  END Q[117]
  PIN Q[116]
    DIRECTION OUTPUT ;
    USE SIGNAL ;
    PORT
      LAYER M4 ;
        RECT 127.4500 195.8000 127.5500 196.4000 ;
    END
  END Q[116]
  PIN Q[115]
    DIRECTION OUTPUT ;
    USE SIGNAL ;
    PORT
      LAYER M4 ;
        RECT 126.6500 195.8000 126.7500 196.4000 ;
    END
  END Q[115]
  PIN Q[114]
    DIRECTION OUTPUT ;
    USE SIGNAL ;
    PORT
      LAYER M4 ;
        RECT 125.8500 195.8000 125.9500 196.4000 ;
    END
  END Q[114]
  PIN Q[113]
    DIRECTION OUTPUT ;
    USE SIGNAL ;
    PORT
      LAYER M4 ;
        RECT 125.0500 195.8000 125.1500 196.4000 ;
    END
  END Q[113]
  PIN Q[112]
    DIRECTION OUTPUT ;
    USE SIGNAL ;
    PORT
      LAYER M4 ;
        RECT 124.2500 195.8000 124.3500 196.4000 ;
    END
  END Q[112]
  PIN Q[111]
    DIRECTION OUTPUT ;
    USE SIGNAL ;
    PORT
      LAYER M4 ;
        RECT 123.4500 195.8000 123.5500 196.4000 ;
    END
  END Q[111]
  PIN Q[110]
    DIRECTION OUTPUT ;
    USE SIGNAL ;
    PORT
      LAYER M4 ;
        RECT 122.6500 195.8000 122.7500 196.4000 ;
    END
  END Q[110]
  PIN Q[109]
    DIRECTION OUTPUT ;
    USE SIGNAL ;
    PORT
      LAYER M4 ;
        RECT 121.8500 195.8000 121.9500 196.4000 ;
    END
  END Q[109]
  PIN Q[108]
    DIRECTION OUTPUT ;
    USE SIGNAL ;
    PORT
      LAYER M4 ;
        RECT 121.0500 195.8000 121.1500 196.4000 ;
    END
  END Q[108]
  PIN Q[107]
    DIRECTION OUTPUT ;
    USE SIGNAL ;
    PORT
      LAYER M4 ;
        RECT 120.2500 195.8000 120.3500 196.4000 ;
    END
  END Q[107]
  PIN Q[106]
    DIRECTION OUTPUT ;
    USE SIGNAL ;
    PORT
      LAYER M4 ;
        RECT 119.4500 195.8000 119.5500 196.4000 ;
    END
  END Q[106]
  PIN Q[105]
    DIRECTION OUTPUT ;
    USE SIGNAL ;
    PORT
      LAYER M4 ;
        RECT 118.6500 195.8000 118.7500 196.4000 ;
    END
  END Q[105]
  PIN Q[104]
    DIRECTION OUTPUT ;
    USE SIGNAL ;
    PORT
      LAYER M4 ;
        RECT 117.8500 195.8000 117.9500 196.4000 ;
    END
  END Q[104]
  PIN Q[103]
    DIRECTION OUTPUT ;
    USE SIGNAL ;
    PORT
      LAYER M4 ;
        RECT 117.0500 195.8000 117.1500 196.4000 ;
    END
  END Q[103]
  PIN Q[102]
    DIRECTION OUTPUT ;
    USE SIGNAL ;
    PORT
      LAYER M4 ;
        RECT 116.2500 195.8000 116.3500 196.4000 ;
    END
  END Q[102]
  PIN Q[101]
    DIRECTION OUTPUT ;
    USE SIGNAL ;
    PORT
      LAYER M4 ;
        RECT 115.4500 195.8000 115.5500 196.4000 ;
    END
  END Q[101]
  PIN Q[100]
    DIRECTION OUTPUT ;
    USE SIGNAL ;
    PORT
      LAYER M4 ;
        RECT 114.6500 195.8000 114.7500 196.4000 ;
    END
  END Q[100]
  PIN Q[99]
    DIRECTION OUTPUT ;
    USE SIGNAL ;
    PORT
      LAYER M4 ;
        RECT 113.8500 195.8000 113.9500 196.4000 ;
    END
  END Q[99]
  PIN Q[98]
    DIRECTION OUTPUT ;
    USE SIGNAL ;
    PORT
      LAYER M4 ;
        RECT 113.0500 195.8000 113.1500 196.4000 ;
    END
  END Q[98]
  PIN Q[97]
    DIRECTION OUTPUT ;
    USE SIGNAL ;
    PORT
      LAYER M4 ;
        RECT 112.2500 195.8000 112.3500 196.4000 ;
    END
  END Q[97]
  PIN Q[96]
    DIRECTION OUTPUT ;
    USE SIGNAL ;
    PORT
      LAYER M4 ;
        RECT 111.4500 195.8000 111.5500 196.4000 ;
    END
  END Q[96]
  PIN Q[95]
    DIRECTION OUTPUT ;
    USE SIGNAL ;
    PORT
      LAYER M4 ;
        RECT 110.6500 195.8000 110.7500 196.4000 ;
    END
  END Q[95]
  PIN Q[94]
    DIRECTION OUTPUT ;
    USE SIGNAL ;
    PORT
      LAYER M4 ;
        RECT 109.8500 195.8000 109.9500 196.4000 ;
    END
  END Q[94]
  PIN Q[93]
    DIRECTION OUTPUT ;
    USE SIGNAL ;
    PORT
      LAYER M4 ;
        RECT 109.0500 195.8000 109.1500 196.4000 ;
    END
  END Q[93]
  PIN Q[92]
    DIRECTION OUTPUT ;
    USE SIGNAL ;
    PORT
      LAYER M4 ;
        RECT 108.2500 195.8000 108.3500 196.4000 ;
    END
  END Q[92]
  PIN Q[91]
    DIRECTION OUTPUT ;
    USE SIGNAL ;
    PORT
      LAYER M4 ;
        RECT 107.4500 195.8000 107.5500 196.4000 ;
    END
  END Q[91]
  PIN Q[90]
    DIRECTION OUTPUT ;
    USE SIGNAL ;
    PORT
      LAYER M4 ;
        RECT 106.6500 195.8000 106.7500 196.4000 ;
    END
  END Q[90]
  PIN Q[89]
    DIRECTION OUTPUT ;
    USE SIGNAL ;
    PORT
      LAYER M4 ;
        RECT 105.8500 195.8000 105.9500 196.4000 ;
    END
  END Q[89]
  PIN Q[88]
    DIRECTION OUTPUT ;
    USE SIGNAL ;
    PORT
      LAYER M4 ;
        RECT 105.0500 195.8000 105.1500 196.4000 ;
    END
  END Q[88]
  PIN Q[87]
    DIRECTION OUTPUT ;
    USE SIGNAL ;
    PORT
      LAYER M4 ;
        RECT 104.2500 195.8000 104.3500 196.4000 ;
    END
  END Q[87]
  PIN Q[86]
    DIRECTION OUTPUT ;
    USE SIGNAL ;
    PORT
      LAYER M4 ;
        RECT 103.4500 195.8000 103.5500 196.4000 ;
    END
  END Q[86]
  PIN Q[85]
    DIRECTION OUTPUT ;
    USE SIGNAL ;
    PORT
      LAYER M4 ;
        RECT 102.6500 195.8000 102.7500 196.4000 ;
    END
  END Q[85]
  PIN Q[84]
    DIRECTION OUTPUT ;
    USE SIGNAL ;
    PORT
      LAYER M4 ;
        RECT 101.8500 195.8000 101.9500 196.4000 ;
    END
  END Q[84]
  PIN Q[83]
    DIRECTION OUTPUT ;
    USE SIGNAL ;
    PORT
      LAYER M4 ;
        RECT 101.0500 195.8000 101.1500 196.4000 ;
    END
  END Q[83]
  PIN Q[82]
    DIRECTION OUTPUT ;
    USE SIGNAL ;
    PORT
      LAYER M4 ;
        RECT 100.2500 195.8000 100.3500 196.4000 ;
    END
  END Q[82]
  PIN Q[81]
    DIRECTION OUTPUT ;
    USE SIGNAL ;
    PORT
      LAYER M4 ;
        RECT 99.4500 195.8000 99.5500 196.4000 ;
    END
  END Q[81]
  PIN Q[80]
    DIRECTION OUTPUT ;
    USE SIGNAL ;
    PORT
      LAYER M4 ;
        RECT 98.6500 195.8000 98.7500 196.4000 ;
    END
  END Q[80]
  PIN Q[79]
    DIRECTION OUTPUT ;
    USE SIGNAL ;
    PORT
      LAYER M4 ;
        RECT 97.8500 195.8000 97.9500 196.4000 ;
    END
  END Q[79]
  PIN Q[78]
    DIRECTION OUTPUT ;
    USE SIGNAL ;
    PORT
      LAYER M4 ;
        RECT 97.0500 195.8000 97.1500 196.4000 ;
    END
  END Q[78]
  PIN Q[77]
    DIRECTION OUTPUT ;
    USE SIGNAL ;
    PORT
      LAYER M4 ;
        RECT 96.2500 195.8000 96.3500 196.4000 ;
    END
  END Q[77]
  PIN Q[76]
    DIRECTION OUTPUT ;
    USE SIGNAL ;
    PORT
      LAYER M4 ;
        RECT 95.4500 195.8000 95.5500 196.4000 ;
    END
  END Q[76]
  PIN Q[75]
    DIRECTION OUTPUT ;
    USE SIGNAL ;
    PORT
      LAYER M4 ;
        RECT 94.6500 195.8000 94.7500 196.4000 ;
    END
  END Q[75]
  PIN Q[74]
    DIRECTION OUTPUT ;
    USE SIGNAL ;
    PORT
      LAYER M4 ;
        RECT 93.8500 195.8000 93.9500 196.4000 ;
    END
  END Q[74]
  PIN Q[73]
    DIRECTION OUTPUT ;
    USE SIGNAL ;
    PORT
      LAYER M4 ;
        RECT 93.0500 195.8000 93.1500 196.4000 ;
    END
  END Q[73]
  PIN Q[72]
    DIRECTION OUTPUT ;
    USE SIGNAL ;
    PORT
      LAYER M4 ;
        RECT 92.2500 195.8000 92.3500 196.4000 ;
    END
  END Q[72]
  PIN Q[71]
    DIRECTION OUTPUT ;
    USE SIGNAL ;
    PORT
      LAYER M4 ;
        RECT 91.4500 195.8000 91.5500 196.4000 ;
    END
  END Q[71]
  PIN Q[70]
    DIRECTION OUTPUT ;
    USE SIGNAL ;
    PORT
      LAYER M4 ;
        RECT 90.6500 195.8000 90.7500 196.4000 ;
    END
  END Q[70]
  PIN Q[69]
    DIRECTION OUTPUT ;
    USE SIGNAL ;
    PORT
      LAYER M4 ;
        RECT 89.8500 195.8000 89.9500 196.4000 ;
    END
  END Q[69]
  PIN Q[68]
    DIRECTION OUTPUT ;
    USE SIGNAL ;
    PORT
      LAYER M4 ;
        RECT 89.0500 195.8000 89.1500 196.4000 ;
    END
  END Q[68]
  PIN Q[67]
    DIRECTION OUTPUT ;
    USE SIGNAL ;
    PORT
      LAYER M4 ;
        RECT 88.2500 195.8000 88.3500 196.4000 ;
    END
  END Q[67]
  PIN Q[66]
    DIRECTION OUTPUT ;
    USE SIGNAL ;
    PORT
      LAYER M4 ;
        RECT 87.4500 195.8000 87.5500 196.4000 ;
    END
  END Q[66]
  PIN Q[65]
    DIRECTION OUTPUT ;
    USE SIGNAL ;
    PORT
      LAYER M4 ;
        RECT 86.6500 195.8000 86.7500 196.4000 ;
    END
  END Q[65]
  PIN Q[64]
    DIRECTION OUTPUT ;
    USE SIGNAL ;
    PORT
      LAYER M4 ;
        RECT 85.8500 195.8000 85.9500 196.4000 ;
    END
  END Q[64]
  PIN Q[63]
    DIRECTION OUTPUT ;
    USE SIGNAL ;
    PORT
      LAYER M4 ;
        RECT 85.0500 195.8000 85.1500 196.4000 ;
    END
  END Q[63]
  PIN Q[62]
    DIRECTION OUTPUT ;
    USE SIGNAL ;
    PORT
      LAYER M4 ;
        RECT 84.2500 195.8000 84.3500 196.4000 ;
    END
  END Q[62]
  PIN Q[61]
    DIRECTION OUTPUT ;
    USE SIGNAL ;
    PORT
      LAYER M4 ;
        RECT 83.4500 195.8000 83.5500 196.4000 ;
    END
  END Q[61]
  PIN Q[60]
    DIRECTION OUTPUT ;
    USE SIGNAL ;
    PORT
      LAYER M4 ;
        RECT 82.6500 195.8000 82.7500 196.4000 ;
    END
  END Q[60]
  PIN Q[59]
    DIRECTION OUTPUT ;
    USE SIGNAL ;
    PORT
      LAYER M4 ;
        RECT 81.8500 195.8000 81.9500 196.4000 ;
    END
  END Q[59]
  PIN Q[58]
    DIRECTION OUTPUT ;
    USE SIGNAL ;
    PORT
      LAYER M4 ;
        RECT 81.0500 195.8000 81.1500 196.4000 ;
    END
  END Q[58]
  PIN Q[57]
    DIRECTION OUTPUT ;
    USE SIGNAL ;
    PORT
      LAYER M4 ;
        RECT 80.2500 195.8000 80.3500 196.4000 ;
    END
  END Q[57]
  PIN Q[56]
    DIRECTION OUTPUT ;
    USE SIGNAL ;
    PORT
      LAYER M4 ;
        RECT 79.4500 195.8000 79.5500 196.4000 ;
    END
  END Q[56]
  PIN Q[55]
    DIRECTION OUTPUT ;
    USE SIGNAL ;
    PORT
      LAYER M4 ;
        RECT 78.6500 195.8000 78.7500 196.4000 ;
    END
  END Q[55]
  PIN Q[54]
    DIRECTION OUTPUT ;
    USE SIGNAL ;
    PORT
      LAYER M4 ;
        RECT 77.8500 195.8000 77.9500 196.4000 ;
    END
  END Q[54]
  PIN Q[53]
    DIRECTION OUTPUT ;
    USE SIGNAL ;
    PORT
      LAYER M4 ;
        RECT 77.0500 195.8000 77.1500 196.4000 ;
    END
  END Q[53]
  PIN Q[52]
    DIRECTION OUTPUT ;
    USE SIGNAL ;
    PORT
      LAYER M4 ;
        RECT 76.2500 195.8000 76.3500 196.4000 ;
    END
  END Q[52]
  PIN Q[51]
    DIRECTION OUTPUT ;
    USE SIGNAL ;
    PORT
      LAYER M4 ;
        RECT 75.4500 195.8000 75.5500 196.4000 ;
    END
  END Q[51]
  PIN Q[50]
    DIRECTION OUTPUT ;
    USE SIGNAL ;
    PORT
      LAYER M4 ;
        RECT 74.6500 195.8000 74.7500 196.4000 ;
    END
  END Q[50]
  PIN Q[49]
    DIRECTION OUTPUT ;
    USE SIGNAL ;
    PORT
      LAYER M4 ;
        RECT 73.8500 195.8000 73.9500 196.4000 ;
    END
  END Q[49]
  PIN Q[48]
    DIRECTION OUTPUT ;
    USE SIGNAL ;
    PORT
      LAYER M4 ;
        RECT 73.0500 195.8000 73.1500 196.4000 ;
    END
  END Q[48]
  PIN Q[47]
    DIRECTION OUTPUT ;
    USE SIGNAL ;
    PORT
      LAYER M4 ;
        RECT 72.2500 195.8000 72.3500 196.4000 ;
    END
  END Q[47]
  PIN Q[46]
    DIRECTION OUTPUT ;
    USE SIGNAL ;
    PORT
      LAYER M4 ;
        RECT 71.4500 195.8000 71.5500 196.4000 ;
    END
  END Q[46]
  PIN Q[45]
    DIRECTION OUTPUT ;
    USE SIGNAL ;
    PORT
      LAYER M4 ;
        RECT 70.6500 195.8000 70.7500 196.4000 ;
    END
  END Q[45]
  PIN Q[44]
    DIRECTION OUTPUT ;
    USE SIGNAL ;
    PORT
      LAYER M4 ;
        RECT 69.8500 195.8000 69.9500 196.4000 ;
    END
  END Q[44]
  PIN Q[43]
    DIRECTION OUTPUT ;
    USE SIGNAL ;
    PORT
      LAYER M4 ;
        RECT 69.0500 195.8000 69.1500 196.4000 ;
    END
  END Q[43]
  PIN Q[42]
    DIRECTION OUTPUT ;
    USE SIGNAL ;
    PORT
      LAYER M4 ;
        RECT 68.2500 195.8000 68.3500 196.4000 ;
    END
  END Q[42]
  PIN Q[41]
    DIRECTION OUTPUT ;
    USE SIGNAL ;
    PORT
      LAYER M4 ;
        RECT 67.4500 195.8000 67.5500 196.4000 ;
    END
  END Q[41]
  PIN Q[40]
    DIRECTION OUTPUT ;
    USE SIGNAL ;
    PORT
      LAYER M4 ;
        RECT 66.6500 195.8000 66.7500 196.4000 ;
    END
  END Q[40]
  PIN Q[39]
    DIRECTION OUTPUT ;
    USE SIGNAL ;
    PORT
      LAYER M4 ;
        RECT 65.8500 195.8000 65.9500 196.4000 ;
    END
  END Q[39]
  PIN Q[38]
    DIRECTION OUTPUT ;
    USE SIGNAL ;
    PORT
      LAYER M4 ;
        RECT 65.0500 195.8000 65.1500 196.4000 ;
    END
  END Q[38]
  PIN Q[37]
    DIRECTION OUTPUT ;
    USE SIGNAL ;
    PORT
      LAYER M4 ;
        RECT 64.2500 195.8000 64.3500 196.4000 ;
    END
  END Q[37]
  PIN Q[36]
    DIRECTION OUTPUT ;
    USE SIGNAL ;
    PORT
      LAYER M4 ;
        RECT 63.4500 195.8000 63.5500 196.4000 ;
    END
  END Q[36]
  PIN Q[35]
    DIRECTION OUTPUT ;
    USE SIGNAL ;
    PORT
      LAYER M4 ;
        RECT 62.6500 195.8000 62.7500 196.4000 ;
    END
  END Q[35]
  PIN Q[34]
    DIRECTION OUTPUT ;
    USE SIGNAL ;
    PORT
      LAYER M4 ;
        RECT 61.8500 195.8000 61.9500 196.4000 ;
    END
  END Q[34]
  PIN Q[33]
    DIRECTION OUTPUT ;
    USE SIGNAL ;
    PORT
      LAYER M4 ;
        RECT 61.0500 195.8000 61.1500 196.4000 ;
    END
  END Q[33]
  PIN Q[32]
    DIRECTION OUTPUT ;
    USE SIGNAL ;
    PORT
      LAYER M4 ;
        RECT 60.2500 195.8000 60.3500 196.4000 ;
    END
  END Q[32]
  PIN Q[31]
    DIRECTION OUTPUT ;
    USE SIGNAL ;
    PORT
      LAYER M4 ;
        RECT 59.4500 195.8000 59.5500 196.4000 ;
    END
  END Q[31]
  PIN Q[30]
    DIRECTION OUTPUT ;
    USE SIGNAL ;
    PORT
      LAYER M4 ;
        RECT 58.6500 195.8000 58.7500 196.4000 ;
    END
  END Q[30]
  PIN Q[29]
    DIRECTION OUTPUT ;
    USE SIGNAL ;
    PORT
      LAYER M4 ;
        RECT 57.8500 195.8000 57.9500 196.4000 ;
    END
  END Q[29]
  PIN Q[28]
    DIRECTION OUTPUT ;
    USE SIGNAL ;
    PORT
      LAYER M4 ;
        RECT 57.0500 195.8000 57.1500 196.4000 ;
    END
  END Q[28]
  PIN Q[27]
    DIRECTION OUTPUT ;
    USE SIGNAL ;
    PORT
      LAYER M4 ;
        RECT 56.2500 195.8000 56.3500 196.4000 ;
    END
  END Q[27]
  PIN Q[26]
    DIRECTION OUTPUT ;
    USE SIGNAL ;
    PORT
      LAYER M4 ;
        RECT 55.4500 195.8000 55.5500 196.4000 ;
    END
  END Q[26]
  PIN Q[25]
    DIRECTION OUTPUT ;
    USE SIGNAL ;
    PORT
      LAYER M4 ;
        RECT 54.6500 195.8000 54.7500 196.4000 ;
    END
  END Q[25]
  PIN Q[24]
    DIRECTION OUTPUT ;
    USE SIGNAL ;
    PORT
      LAYER M4 ;
        RECT 53.8500 195.8000 53.9500 196.4000 ;
    END
  END Q[24]
  PIN Q[23]
    DIRECTION OUTPUT ;
    USE SIGNAL ;
    PORT
      LAYER M4 ;
        RECT 53.0500 195.8000 53.1500 196.4000 ;
    END
  END Q[23]
  PIN Q[22]
    DIRECTION OUTPUT ;
    USE SIGNAL ;
    PORT
      LAYER M4 ;
        RECT 52.2500 195.8000 52.3500 196.4000 ;
    END
  END Q[22]
  PIN Q[21]
    DIRECTION OUTPUT ;
    USE SIGNAL ;
    PORT
      LAYER M4 ;
        RECT 51.4500 195.8000 51.5500 196.4000 ;
    END
  END Q[21]
  PIN Q[20]
    DIRECTION OUTPUT ;
    USE SIGNAL ;
    PORT
      LAYER M4 ;
        RECT 50.6500 195.8000 50.7500 196.4000 ;
    END
  END Q[20]
  PIN Q[19]
    DIRECTION OUTPUT ;
    USE SIGNAL ;
    PORT
      LAYER M4 ;
        RECT 49.8500 195.8000 49.9500 196.4000 ;
    END
  END Q[19]
  PIN Q[18]
    DIRECTION OUTPUT ;
    USE SIGNAL ;
    PORT
      LAYER M4 ;
        RECT 49.0500 195.8000 49.1500 196.4000 ;
    END
  END Q[18]
  PIN Q[17]
    DIRECTION OUTPUT ;
    USE SIGNAL ;
    PORT
      LAYER M4 ;
        RECT 48.2500 195.8000 48.3500 196.4000 ;
    END
  END Q[17]
  PIN Q[16]
    DIRECTION OUTPUT ;
    USE SIGNAL ;
    PORT
      LAYER M4 ;
        RECT 47.4500 195.8000 47.5500 196.4000 ;
    END
  END Q[16]
  PIN Q[15]
    DIRECTION OUTPUT ;
    USE SIGNAL ;
    PORT
      LAYER M4 ;
        RECT 46.6500 195.8000 46.7500 196.4000 ;
    END
  END Q[15]
  PIN Q[14]
    DIRECTION OUTPUT ;
    USE SIGNAL ;
    PORT
      LAYER M4 ;
        RECT 45.8500 195.8000 45.9500 196.4000 ;
    END
  END Q[14]
  PIN Q[13]
    DIRECTION OUTPUT ;
    USE SIGNAL ;
    PORT
      LAYER M4 ;
        RECT 45.0500 195.8000 45.1500 196.4000 ;
    END
  END Q[13]
  PIN Q[12]
    DIRECTION OUTPUT ;
    USE SIGNAL ;
    PORT
      LAYER M4 ;
        RECT 44.2500 195.8000 44.3500 196.4000 ;
    END
  END Q[12]
  PIN Q[11]
    DIRECTION OUTPUT ;
    USE SIGNAL ;
    PORT
      LAYER M4 ;
        RECT 43.4500 195.8000 43.5500 196.4000 ;
    END
  END Q[11]
  PIN Q[10]
    DIRECTION OUTPUT ;
    USE SIGNAL ;
    PORT
      LAYER M4 ;
        RECT 42.6500 195.8000 42.7500 196.4000 ;
    END
  END Q[10]
  PIN Q[9]
    DIRECTION OUTPUT ;
    USE SIGNAL ;
    PORT
      LAYER M4 ;
        RECT 41.8500 195.8000 41.9500 196.4000 ;
    END
  END Q[9]
  PIN Q[8]
    DIRECTION OUTPUT ;
    USE SIGNAL ;
    PORT
      LAYER M4 ;
        RECT 41.0500 195.8000 41.1500 196.4000 ;
    END
  END Q[8]
  PIN Q[7]
    DIRECTION OUTPUT ;
    USE SIGNAL ;
    PORT
      LAYER M4 ;
        RECT 40.2500 195.8000 40.3500 196.4000 ;
    END
  END Q[7]
  PIN Q[6]
    DIRECTION OUTPUT ;
    USE SIGNAL ;
    PORT
      LAYER M4 ;
        RECT 39.4500 195.8000 39.5500 196.4000 ;
    END
  END Q[6]
  PIN Q[5]
    DIRECTION OUTPUT ;
    USE SIGNAL ;
    PORT
      LAYER M4 ;
        RECT 38.6500 195.8000 38.7500 196.4000 ;
    END
  END Q[5]
  PIN Q[4]
    DIRECTION OUTPUT ;
    USE SIGNAL ;
    PORT
      LAYER M4 ;
        RECT 37.8500 195.8000 37.9500 196.4000 ;
    END
  END Q[4]
  PIN Q[3]
    DIRECTION OUTPUT ;
    USE SIGNAL ;
    PORT
      LAYER M4 ;
        RECT 37.0500 195.8000 37.1500 196.4000 ;
    END
  END Q[3]
  PIN Q[2]
    DIRECTION OUTPUT ;
    USE SIGNAL ;
    PORT
      LAYER M4 ;
        RECT 36.2500 195.8000 36.3500 196.4000 ;
    END
  END Q[2]
  PIN Q[1]
    DIRECTION OUTPUT ;
    USE SIGNAL ;
    PORT
      LAYER M4 ;
        RECT 35.4500 195.8000 35.5500 196.4000 ;
    END
  END Q[1]
  PIN Q[0]
    DIRECTION OUTPUT ;
    USE SIGNAL ;
    PORT
      LAYER M4 ;
        RECT 34.6500 195.8000 34.7500 196.4000 ;
    END
  END Q[0]
  PIN CEN
    DIRECTION INPUT ;
    USE SIGNAL ;
    PORT
      LAYER M3 ;
        RECT 0.0000 97.1500 0.6000 97.2500 ;
    END
  END CEN
  PIN WEN
    DIRECTION INPUT ;
    USE SIGNAL ;
    PORT
      LAYER M3 ;
        RECT 0.0000 100.3500 0.6000 100.4500 ;
    END
  END WEN
  PIN A[2]
    DIRECTION INPUT ;
    USE SIGNAL ;
    PORT
      LAYER M3 ;
        RECT 0.0000 97.9500 0.6000 98.0500 ;
    END
  END A[2]
  PIN A[1]
    DIRECTION INPUT ;
    USE SIGNAL ;
    PORT
      LAYER M3 ;
        RECT 0.0000 98.7500 0.6000 98.8500 ;
    END
  END A[1]
  PIN A[0]
    DIRECTION INPUT ;
    USE SIGNAL ;
    PORT
      LAYER M3 ;
        RECT 0.0000 99.5500 0.6000 99.6500 ;
    END
  END A[0]
  OBS
    LAYER M1 ;
      RECT 0.0000 0.0000 197.0000 196.4000 ;
    LAYER M2 ;
      RECT 0.0000 0.0000 197.0000 196.4000 ;
    LAYER M3 ;
      RECT 0.0000 100.5500 197.0000 196.4000 ;
      RECT 0.7000 100.2500 197.0000 100.5500 ;
      RECT 0.0000 99.7500 197.0000 100.2500 ;
      RECT 0.7000 99.4500 197.0000 99.7500 ;
      RECT 0.0000 98.9500 197.0000 99.4500 ;
      RECT 0.7000 98.6500 197.0000 98.9500 ;
      RECT 0.0000 98.1500 197.0000 98.6500 ;
      RECT 0.7000 97.8500 197.0000 98.1500 ;
      RECT 0.0000 97.3500 197.0000 97.8500 ;
      RECT 0.7000 97.0500 197.0000 97.3500 ;
      RECT 0.0000 96.5500 197.0000 97.0500 ;
      RECT 0.7000 96.2500 197.0000 96.5500 ;
      RECT 0.0000 0.0000 197.0000 96.2500 ;
    LAYER M4 ;
      RECT 162.0500 195.7000 197.0000 196.4000 ;
      RECT 161.2500 195.7000 161.7500 196.4000 ;
      RECT 160.4500 195.7000 160.9500 196.4000 ;
      RECT 159.6500 195.7000 160.1500 196.4000 ;
      RECT 158.8500 195.7000 159.3500 196.4000 ;
      RECT 158.0500 195.7000 158.5500 196.4000 ;
      RECT 157.2500 195.7000 157.7500 196.4000 ;
      RECT 156.4500 195.7000 156.9500 196.4000 ;
      RECT 155.6500 195.7000 156.1500 196.4000 ;
      RECT 154.8500 195.7000 155.3500 196.4000 ;
      RECT 154.0500 195.7000 154.5500 196.4000 ;
      RECT 153.2500 195.7000 153.7500 196.4000 ;
      RECT 152.4500 195.7000 152.9500 196.4000 ;
      RECT 151.6500 195.7000 152.1500 196.4000 ;
      RECT 150.8500 195.7000 151.3500 196.4000 ;
      RECT 150.0500 195.7000 150.5500 196.4000 ;
      RECT 149.2500 195.7000 149.7500 196.4000 ;
      RECT 148.4500 195.7000 148.9500 196.4000 ;
      RECT 147.6500 195.7000 148.1500 196.4000 ;
      RECT 146.8500 195.7000 147.3500 196.4000 ;
      RECT 146.0500 195.7000 146.5500 196.4000 ;
      RECT 145.2500 195.7000 145.7500 196.4000 ;
      RECT 144.4500 195.7000 144.9500 196.4000 ;
      RECT 143.6500 195.7000 144.1500 196.4000 ;
      RECT 142.8500 195.7000 143.3500 196.4000 ;
      RECT 142.0500 195.7000 142.5500 196.4000 ;
      RECT 141.2500 195.7000 141.7500 196.4000 ;
      RECT 140.4500 195.7000 140.9500 196.4000 ;
      RECT 139.6500 195.7000 140.1500 196.4000 ;
      RECT 138.8500 195.7000 139.3500 196.4000 ;
      RECT 138.0500 195.7000 138.5500 196.4000 ;
      RECT 137.2500 195.7000 137.7500 196.4000 ;
      RECT 136.4500 195.7000 136.9500 196.4000 ;
      RECT 135.6500 195.7000 136.1500 196.4000 ;
      RECT 134.8500 195.7000 135.3500 196.4000 ;
      RECT 134.0500 195.7000 134.5500 196.4000 ;
      RECT 133.2500 195.7000 133.7500 196.4000 ;
      RECT 132.4500 195.7000 132.9500 196.4000 ;
      RECT 131.6500 195.7000 132.1500 196.4000 ;
      RECT 130.8500 195.7000 131.3500 196.4000 ;
      RECT 130.0500 195.7000 130.5500 196.4000 ;
      RECT 129.2500 195.7000 129.7500 196.4000 ;
      RECT 128.4500 195.7000 128.9500 196.4000 ;
      RECT 127.6500 195.7000 128.1500 196.4000 ;
      RECT 126.8500 195.7000 127.3500 196.4000 ;
      RECT 126.0500 195.7000 126.5500 196.4000 ;
      RECT 125.2500 195.7000 125.7500 196.4000 ;
      RECT 124.4500 195.7000 124.9500 196.4000 ;
      RECT 123.6500 195.7000 124.1500 196.4000 ;
      RECT 122.8500 195.7000 123.3500 196.4000 ;
      RECT 122.0500 195.7000 122.5500 196.4000 ;
      RECT 121.2500 195.7000 121.7500 196.4000 ;
      RECT 120.4500 195.7000 120.9500 196.4000 ;
      RECT 119.6500 195.7000 120.1500 196.4000 ;
      RECT 118.8500 195.7000 119.3500 196.4000 ;
      RECT 118.0500 195.7000 118.5500 196.4000 ;
      RECT 117.2500 195.7000 117.7500 196.4000 ;
      RECT 116.4500 195.7000 116.9500 196.4000 ;
      RECT 115.6500 195.7000 116.1500 196.4000 ;
      RECT 114.8500 195.7000 115.3500 196.4000 ;
      RECT 114.0500 195.7000 114.5500 196.4000 ;
      RECT 113.2500 195.7000 113.7500 196.4000 ;
      RECT 112.4500 195.7000 112.9500 196.4000 ;
      RECT 111.6500 195.7000 112.1500 196.4000 ;
      RECT 110.8500 195.7000 111.3500 196.4000 ;
      RECT 110.0500 195.7000 110.5500 196.4000 ;
      RECT 109.2500 195.7000 109.7500 196.4000 ;
      RECT 108.4500 195.7000 108.9500 196.4000 ;
      RECT 107.6500 195.7000 108.1500 196.4000 ;
      RECT 106.8500 195.7000 107.3500 196.4000 ;
      RECT 106.0500 195.7000 106.5500 196.4000 ;
      RECT 105.2500 195.7000 105.7500 196.4000 ;
      RECT 104.4500 195.7000 104.9500 196.4000 ;
      RECT 103.6500 195.7000 104.1500 196.4000 ;
      RECT 102.8500 195.7000 103.3500 196.4000 ;
      RECT 102.0500 195.7000 102.5500 196.4000 ;
      RECT 101.2500 195.7000 101.7500 196.4000 ;
      RECT 100.4500 195.7000 100.9500 196.4000 ;
      RECT 99.6500 195.7000 100.1500 196.4000 ;
      RECT 98.8500 195.7000 99.3500 196.4000 ;
      RECT 98.0500 195.7000 98.5500 196.4000 ;
      RECT 97.2500 195.7000 97.7500 196.4000 ;
      RECT 96.4500 195.7000 96.9500 196.4000 ;
      RECT 95.6500 195.7000 96.1500 196.4000 ;
      RECT 94.8500 195.7000 95.3500 196.4000 ;
      RECT 94.0500 195.7000 94.5500 196.4000 ;
      RECT 93.2500 195.7000 93.7500 196.4000 ;
      RECT 92.4500 195.7000 92.9500 196.4000 ;
      RECT 91.6500 195.7000 92.1500 196.4000 ;
      RECT 90.8500 195.7000 91.3500 196.4000 ;
      RECT 90.0500 195.7000 90.5500 196.4000 ;
      RECT 89.2500 195.7000 89.7500 196.4000 ;
      RECT 88.4500 195.7000 88.9500 196.4000 ;
      RECT 87.6500 195.7000 88.1500 196.4000 ;
      RECT 86.8500 195.7000 87.3500 196.4000 ;
      RECT 86.0500 195.7000 86.5500 196.4000 ;
      RECT 85.2500 195.7000 85.7500 196.4000 ;
      RECT 84.4500 195.7000 84.9500 196.4000 ;
      RECT 83.6500 195.7000 84.1500 196.4000 ;
      RECT 82.8500 195.7000 83.3500 196.4000 ;
      RECT 82.0500 195.7000 82.5500 196.4000 ;
      RECT 81.2500 195.7000 81.7500 196.4000 ;
      RECT 80.4500 195.7000 80.9500 196.4000 ;
      RECT 79.6500 195.7000 80.1500 196.4000 ;
      RECT 78.8500 195.7000 79.3500 196.4000 ;
      RECT 78.0500 195.7000 78.5500 196.4000 ;
      RECT 77.2500 195.7000 77.7500 196.4000 ;
      RECT 76.4500 195.7000 76.9500 196.4000 ;
      RECT 75.6500 195.7000 76.1500 196.4000 ;
      RECT 74.8500 195.7000 75.3500 196.4000 ;
      RECT 74.0500 195.7000 74.5500 196.4000 ;
      RECT 73.2500 195.7000 73.7500 196.4000 ;
      RECT 72.4500 195.7000 72.9500 196.4000 ;
      RECT 71.6500 195.7000 72.1500 196.4000 ;
      RECT 70.8500 195.7000 71.3500 196.4000 ;
      RECT 70.0500 195.7000 70.5500 196.4000 ;
      RECT 69.2500 195.7000 69.7500 196.4000 ;
      RECT 68.4500 195.7000 68.9500 196.4000 ;
      RECT 67.6500 195.7000 68.1500 196.4000 ;
      RECT 66.8500 195.7000 67.3500 196.4000 ;
      RECT 66.0500 195.7000 66.5500 196.4000 ;
      RECT 65.2500 195.7000 65.7500 196.4000 ;
      RECT 64.4500 195.7000 64.9500 196.4000 ;
      RECT 63.6500 195.7000 64.1500 196.4000 ;
      RECT 62.8500 195.7000 63.3500 196.4000 ;
      RECT 62.0500 195.7000 62.5500 196.4000 ;
      RECT 61.2500 195.7000 61.7500 196.4000 ;
      RECT 60.4500 195.7000 60.9500 196.4000 ;
      RECT 59.6500 195.7000 60.1500 196.4000 ;
      RECT 58.8500 195.7000 59.3500 196.4000 ;
      RECT 58.0500 195.7000 58.5500 196.4000 ;
      RECT 57.2500 195.7000 57.7500 196.4000 ;
      RECT 56.4500 195.7000 56.9500 196.4000 ;
      RECT 55.6500 195.7000 56.1500 196.4000 ;
      RECT 54.8500 195.7000 55.3500 196.4000 ;
      RECT 54.0500 195.7000 54.5500 196.4000 ;
      RECT 53.2500 195.7000 53.7500 196.4000 ;
      RECT 52.4500 195.7000 52.9500 196.4000 ;
      RECT 51.6500 195.7000 52.1500 196.4000 ;
      RECT 50.8500 195.7000 51.3500 196.4000 ;
      RECT 50.0500 195.7000 50.5500 196.4000 ;
      RECT 49.2500 195.7000 49.7500 196.4000 ;
      RECT 48.4500 195.7000 48.9500 196.4000 ;
      RECT 47.6500 195.7000 48.1500 196.4000 ;
      RECT 46.8500 195.7000 47.3500 196.4000 ;
      RECT 46.0500 195.7000 46.5500 196.4000 ;
      RECT 45.2500 195.7000 45.7500 196.4000 ;
      RECT 44.4500 195.7000 44.9500 196.4000 ;
      RECT 43.6500 195.7000 44.1500 196.4000 ;
      RECT 42.8500 195.7000 43.3500 196.4000 ;
      RECT 42.0500 195.7000 42.5500 196.4000 ;
      RECT 41.2500 195.7000 41.7500 196.4000 ;
      RECT 40.4500 195.7000 40.9500 196.4000 ;
      RECT 39.6500 195.7000 40.1500 196.4000 ;
      RECT 38.8500 195.7000 39.3500 196.4000 ;
      RECT 38.0500 195.7000 38.5500 196.4000 ;
      RECT 37.2500 195.7000 37.7500 196.4000 ;
      RECT 36.4500 195.7000 36.9500 196.4000 ;
      RECT 35.6500 195.7000 36.1500 196.4000 ;
      RECT 34.8500 195.7000 35.3500 196.4000 ;
      RECT 0.0000 195.7000 34.5500 196.4000 ;
      RECT 0.0000 0.7000 197.0000 195.7000 ;
      RECT 162.0500 0.0000 197.0000 0.7000 ;
      RECT 161.2500 0.0000 161.7500 0.7000 ;
      RECT 160.4500 0.0000 160.9500 0.7000 ;
      RECT 159.6500 0.0000 160.1500 0.7000 ;
      RECT 158.8500 0.0000 159.3500 0.7000 ;
      RECT 158.0500 0.0000 158.5500 0.7000 ;
      RECT 157.2500 0.0000 157.7500 0.7000 ;
      RECT 156.4500 0.0000 156.9500 0.7000 ;
      RECT 155.6500 0.0000 156.1500 0.7000 ;
      RECT 154.8500 0.0000 155.3500 0.7000 ;
      RECT 154.0500 0.0000 154.5500 0.7000 ;
      RECT 153.2500 0.0000 153.7500 0.7000 ;
      RECT 152.4500 0.0000 152.9500 0.7000 ;
      RECT 151.6500 0.0000 152.1500 0.7000 ;
      RECT 150.8500 0.0000 151.3500 0.7000 ;
      RECT 150.0500 0.0000 150.5500 0.7000 ;
      RECT 149.2500 0.0000 149.7500 0.7000 ;
      RECT 148.4500 0.0000 148.9500 0.7000 ;
      RECT 147.6500 0.0000 148.1500 0.7000 ;
      RECT 146.8500 0.0000 147.3500 0.7000 ;
      RECT 146.0500 0.0000 146.5500 0.7000 ;
      RECT 145.2500 0.0000 145.7500 0.7000 ;
      RECT 144.4500 0.0000 144.9500 0.7000 ;
      RECT 143.6500 0.0000 144.1500 0.7000 ;
      RECT 142.8500 0.0000 143.3500 0.7000 ;
      RECT 142.0500 0.0000 142.5500 0.7000 ;
      RECT 141.2500 0.0000 141.7500 0.7000 ;
      RECT 140.4500 0.0000 140.9500 0.7000 ;
      RECT 139.6500 0.0000 140.1500 0.7000 ;
      RECT 138.8500 0.0000 139.3500 0.7000 ;
      RECT 138.0500 0.0000 138.5500 0.7000 ;
      RECT 137.2500 0.0000 137.7500 0.7000 ;
      RECT 136.4500 0.0000 136.9500 0.7000 ;
      RECT 135.6500 0.0000 136.1500 0.7000 ;
      RECT 134.8500 0.0000 135.3500 0.7000 ;
      RECT 134.0500 0.0000 134.5500 0.7000 ;
      RECT 133.2500 0.0000 133.7500 0.7000 ;
      RECT 132.4500 0.0000 132.9500 0.7000 ;
      RECT 131.6500 0.0000 132.1500 0.7000 ;
      RECT 130.8500 0.0000 131.3500 0.7000 ;
      RECT 130.0500 0.0000 130.5500 0.7000 ;
      RECT 129.2500 0.0000 129.7500 0.7000 ;
      RECT 128.4500 0.0000 128.9500 0.7000 ;
      RECT 127.6500 0.0000 128.1500 0.7000 ;
      RECT 126.8500 0.0000 127.3500 0.7000 ;
      RECT 126.0500 0.0000 126.5500 0.7000 ;
      RECT 125.2500 0.0000 125.7500 0.7000 ;
      RECT 124.4500 0.0000 124.9500 0.7000 ;
      RECT 123.6500 0.0000 124.1500 0.7000 ;
      RECT 122.8500 0.0000 123.3500 0.7000 ;
      RECT 122.0500 0.0000 122.5500 0.7000 ;
      RECT 121.2500 0.0000 121.7500 0.7000 ;
      RECT 120.4500 0.0000 120.9500 0.7000 ;
      RECT 119.6500 0.0000 120.1500 0.7000 ;
      RECT 118.8500 0.0000 119.3500 0.7000 ;
      RECT 118.0500 0.0000 118.5500 0.7000 ;
      RECT 117.2500 0.0000 117.7500 0.7000 ;
      RECT 116.4500 0.0000 116.9500 0.7000 ;
      RECT 115.6500 0.0000 116.1500 0.7000 ;
      RECT 114.8500 0.0000 115.3500 0.7000 ;
      RECT 114.0500 0.0000 114.5500 0.7000 ;
      RECT 113.2500 0.0000 113.7500 0.7000 ;
      RECT 112.4500 0.0000 112.9500 0.7000 ;
      RECT 111.6500 0.0000 112.1500 0.7000 ;
      RECT 110.8500 0.0000 111.3500 0.7000 ;
      RECT 110.0500 0.0000 110.5500 0.7000 ;
      RECT 109.2500 0.0000 109.7500 0.7000 ;
      RECT 108.4500 0.0000 108.9500 0.7000 ;
      RECT 107.6500 0.0000 108.1500 0.7000 ;
      RECT 106.8500 0.0000 107.3500 0.7000 ;
      RECT 106.0500 0.0000 106.5500 0.7000 ;
      RECT 105.2500 0.0000 105.7500 0.7000 ;
      RECT 104.4500 0.0000 104.9500 0.7000 ;
      RECT 103.6500 0.0000 104.1500 0.7000 ;
      RECT 102.8500 0.0000 103.3500 0.7000 ;
      RECT 102.0500 0.0000 102.5500 0.7000 ;
      RECT 101.2500 0.0000 101.7500 0.7000 ;
      RECT 100.4500 0.0000 100.9500 0.7000 ;
      RECT 99.6500 0.0000 100.1500 0.7000 ;
      RECT 98.8500 0.0000 99.3500 0.7000 ;
      RECT 98.0500 0.0000 98.5500 0.7000 ;
      RECT 97.2500 0.0000 97.7500 0.7000 ;
      RECT 96.4500 0.0000 96.9500 0.7000 ;
      RECT 95.6500 0.0000 96.1500 0.7000 ;
      RECT 94.8500 0.0000 95.3500 0.7000 ;
      RECT 94.0500 0.0000 94.5500 0.7000 ;
      RECT 93.2500 0.0000 93.7500 0.7000 ;
      RECT 92.4500 0.0000 92.9500 0.7000 ;
      RECT 91.6500 0.0000 92.1500 0.7000 ;
      RECT 90.8500 0.0000 91.3500 0.7000 ;
      RECT 90.0500 0.0000 90.5500 0.7000 ;
      RECT 89.2500 0.0000 89.7500 0.7000 ;
      RECT 88.4500 0.0000 88.9500 0.7000 ;
      RECT 87.6500 0.0000 88.1500 0.7000 ;
      RECT 86.8500 0.0000 87.3500 0.7000 ;
      RECT 86.0500 0.0000 86.5500 0.7000 ;
      RECT 85.2500 0.0000 85.7500 0.7000 ;
      RECT 84.4500 0.0000 84.9500 0.7000 ;
      RECT 83.6500 0.0000 84.1500 0.7000 ;
      RECT 82.8500 0.0000 83.3500 0.7000 ;
      RECT 82.0500 0.0000 82.5500 0.7000 ;
      RECT 81.2500 0.0000 81.7500 0.7000 ;
      RECT 80.4500 0.0000 80.9500 0.7000 ;
      RECT 79.6500 0.0000 80.1500 0.7000 ;
      RECT 78.8500 0.0000 79.3500 0.7000 ;
      RECT 78.0500 0.0000 78.5500 0.7000 ;
      RECT 77.2500 0.0000 77.7500 0.7000 ;
      RECT 76.4500 0.0000 76.9500 0.7000 ;
      RECT 75.6500 0.0000 76.1500 0.7000 ;
      RECT 74.8500 0.0000 75.3500 0.7000 ;
      RECT 74.0500 0.0000 74.5500 0.7000 ;
      RECT 73.2500 0.0000 73.7500 0.7000 ;
      RECT 72.4500 0.0000 72.9500 0.7000 ;
      RECT 71.6500 0.0000 72.1500 0.7000 ;
      RECT 70.8500 0.0000 71.3500 0.7000 ;
      RECT 70.0500 0.0000 70.5500 0.7000 ;
      RECT 69.2500 0.0000 69.7500 0.7000 ;
      RECT 68.4500 0.0000 68.9500 0.7000 ;
      RECT 67.6500 0.0000 68.1500 0.7000 ;
      RECT 66.8500 0.0000 67.3500 0.7000 ;
      RECT 66.0500 0.0000 66.5500 0.7000 ;
      RECT 65.2500 0.0000 65.7500 0.7000 ;
      RECT 64.4500 0.0000 64.9500 0.7000 ;
      RECT 63.6500 0.0000 64.1500 0.7000 ;
      RECT 62.8500 0.0000 63.3500 0.7000 ;
      RECT 62.0500 0.0000 62.5500 0.7000 ;
      RECT 61.2500 0.0000 61.7500 0.7000 ;
      RECT 60.4500 0.0000 60.9500 0.7000 ;
      RECT 59.6500 0.0000 60.1500 0.7000 ;
      RECT 58.8500 0.0000 59.3500 0.7000 ;
      RECT 58.0500 0.0000 58.5500 0.7000 ;
      RECT 57.2500 0.0000 57.7500 0.7000 ;
      RECT 56.4500 0.0000 56.9500 0.7000 ;
      RECT 55.6500 0.0000 56.1500 0.7000 ;
      RECT 54.8500 0.0000 55.3500 0.7000 ;
      RECT 54.0500 0.0000 54.5500 0.7000 ;
      RECT 53.2500 0.0000 53.7500 0.7000 ;
      RECT 52.4500 0.0000 52.9500 0.7000 ;
      RECT 51.6500 0.0000 52.1500 0.7000 ;
      RECT 50.8500 0.0000 51.3500 0.7000 ;
      RECT 50.0500 0.0000 50.5500 0.7000 ;
      RECT 49.2500 0.0000 49.7500 0.7000 ;
      RECT 48.4500 0.0000 48.9500 0.7000 ;
      RECT 47.6500 0.0000 48.1500 0.7000 ;
      RECT 46.8500 0.0000 47.3500 0.7000 ;
      RECT 46.0500 0.0000 46.5500 0.7000 ;
      RECT 45.2500 0.0000 45.7500 0.7000 ;
      RECT 44.4500 0.0000 44.9500 0.7000 ;
      RECT 43.6500 0.0000 44.1500 0.7000 ;
      RECT 42.8500 0.0000 43.3500 0.7000 ;
      RECT 42.0500 0.0000 42.5500 0.7000 ;
      RECT 41.2500 0.0000 41.7500 0.7000 ;
      RECT 40.4500 0.0000 40.9500 0.7000 ;
      RECT 39.6500 0.0000 40.1500 0.7000 ;
      RECT 38.8500 0.0000 39.3500 0.7000 ;
      RECT 38.0500 0.0000 38.5500 0.7000 ;
      RECT 37.2500 0.0000 37.7500 0.7000 ;
      RECT 36.4500 0.0000 36.9500 0.7000 ;
      RECT 35.6500 0.0000 36.1500 0.7000 ;
      RECT 34.8500 0.0000 35.3500 0.7000 ;
      RECT 0.0000 0.0000 34.5500 0.7000 ;
    LAYER M5 ;
      RECT 0.0000 0.0000 197.0000 196.4000 ;
    LAYER M6 ;
      RECT 0.0000 0.0000 197.0000 196.4000 ;
    LAYER M7 ;
      RECT 0.0000 0.0000 197.0000 196.4000 ;
    LAYER M8 ;
      RECT 0.0000 0.0000 197.0000 196.4000 ;
  END
END sram_w8

END LIBRARY
